VERSION 5.7 ;
  NOWIREEXTENSIONATPIN ON ;
  DIVIDERCHAR "/" ;
  BUSBITCHARS "[]" ;
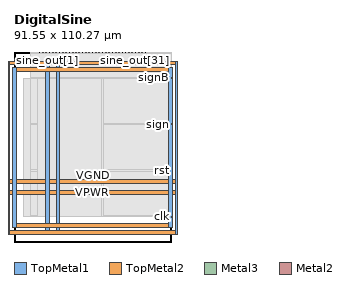
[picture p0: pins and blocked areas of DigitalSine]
MACRO DigitalSine
  CLASS BLOCK ;
  FOREIGN DigitalSine ;
  ORIGIN 0.000 0.000 ;
  SIZE 91.550 BY 110.270 ;
  PIN VGND
    DIRECTION INOUT ;
    USE GROUND ;
    PORT
      LAYER TopMetal1 ;
        RECT -4.740 4.620 -2.740 105.000 ;
    END
    PORT
      LAYER TopMetal2 ;
        RECT -4.740 4.620 95.940 6.620 ;
    END
    PORT
      LAYER TopMetal2 ;
        RECT -4.740 103.000 95.940 105.000 ;
    END
    PORT
      LAYER TopMetal1 ;
        RECT 93.940 4.620 95.940 105.000 ;
    END
    PORT
      LAYER TopMetal1 ;
        RECT 24.460 4.620 26.660 105.000 ;
    END
    PORT
      LAYER TopMetal2 ;
        RECT -4.740 33.820 95.940 36.020 ;
    END
  END VGND
  PIN VPWR
    DIRECTION INOUT ;
    USE POWER ;
    PORT
      LAYER TopMetal1 ;
        RECT -0.740 8.620 1.260 101.000 ;
    END
    PORT
      LAYER TopMetal2 ;
        RECT -0.740 8.620 91.940 10.620 ;
    END
    PORT
      LAYER TopMetal2 ;
        RECT -0.740 99.000 91.940 101.000 ;
    END
    PORT
      LAYER TopMetal1 ;
        RECT 89.940 8.620 91.940 101.000 ;
    END
    PORT
      LAYER TopMetal1 ;
        RECT 18.260 4.620 20.460 105.000 ;
    END
    PORT
      LAYER TopMetal2 ;
        RECT -4.740 27.620 95.940 29.820 ;
    END
  END VPWR
  PIN clk
    DIRECTION INPUT ;
    USE SIGNAL ;
    ANTENNAGATEAREA 0.725400 ;
    PORT
      LAYER Metal3 ;
        RECT 91.150 14.500 91.550 14.900 ;
    END
  END clk
  PIN rst
    DIRECTION INPUT ;
    USE SIGNAL ;
    ANTENNAGATEAREA 0.180700 ;
    PORT
      LAYER Metal3 ;
        RECT 91.150 41.380 91.550 41.780 ;
    END
  END rst
  PIN sign
    DIRECTION OUTPUT ;
    USE SIGNAL ;
    ANTENNADIFFAREA 0.708600 ;
    PORT
      LAYER Metal3 ;
        RECT 91.150 68.260 91.550 68.660 ;
    END
  END sign
  PIN signB
    DIRECTION OUTPUT ;
    USE SIGNAL ;
    ANTENNADIFFAREA 0.708600 ;
    PORT
      LAYER Metal3 ;
        RECT 91.150 95.140 91.550 95.540 ;
    END
  END signB
  PIN sine_out[0]
    DIRECTION OUTPUT ;
    USE SIGNAL ;
    ANTENNADIFFAREA 0.708600 ;
    PORT
      LAYER Metal2 ;
        RECT 14.680 109.870 15.080 110.270 ;
    END
  END sine_out[0]
  PIN sine_out[10]
    DIRECTION OUTPUT ;
    USE SIGNAL ;
    ANTENNADIFFAREA 0.708600 ;
    PORT
      LAYER Metal2 ;
        RECT 33.880 109.870 34.280 110.270 ;
    END
  END sine_out[10]
  PIN sine_out[11]
    DIRECTION OUTPUT ;
    USE SIGNAL ;
    ANTENNADIFFAREA 0.708600 ;
    PORT
      LAYER Metal2 ;
        RECT 35.800 109.870 36.200 110.270 ;
    END
  END sine_out[11]
  PIN sine_out[12]
    DIRECTION OUTPUT ;
    USE SIGNAL ;
    ANTENNADIFFAREA 0.708600 ;
    PORT
      LAYER Metal2 ;
        RECT 37.720 109.870 38.120 110.270 ;
    END
  END sine_out[12]
  PIN sine_out[13]
    DIRECTION OUTPUT ;
    USE SIGNAL ;
    ANTENNADIFFAREA 0.708600 ;
    PORT
      LAYER Metal2 ;
        RECT 39.640 109.870 40.040 110.270 ;
    END
  END sine_out[13]
  PIN sine_out[14]
    DIRECTION OUTPUT ;
    USE SIGNAL ;
    ANTENNADIFFAREA 0.708600 ;
    PORT
      LAYER Metal2 ;
        RECT 41.560 109.870 41.960 110.270 ;
    END
  END sine_out[14]
  PIN sine_out[15]
    DIRECTION OUTPUT ;
    USE SIGNAL ;
    ANTENNADIFFAREA 0.708600 ;
    PORT
      LAYER Metal2 ;
        RECT 43.480 109.870 43.880 110.270 ;
    END
  END sine_out[15]
  PIN sine_out[16]
    DIRECTION OUTPUT ;
    USE SIGNAL ;
    ANTENNADIFFAREA 0.708600 ;
    PORT
      LAYER Metal2 ;
        RECT 45.400 109.870 45.800 110.270 ;
    END
  END sine_out[16]
  PIN sine_out[17]
    DIRECTION OUTPUT ;
    USE SIGNAL ;
    ANTENNADIFFAREA 0.708600 ;
    PORT
      LAYER Metal2 ;
        RECT 47.320 109.870 47.720 110.270 ;
    END
  END sine_out[17]
  PIN sine_out[18]
    DIRECTION OUTPUT ;
    USE SIGNAL ;
    ANTENNADIFFAREA 0.708600 ;
    PORT
      LAYER Metal2 ;
        RECT 49.240 109.870 49.640 110.270 ;
    END
  END sine_out[18]
  PIN sine_out[19]
    DIRECTION OUTPUT ;
    USE SIGNAL ;
    ANTENNADIFFAREA 0.708600 ;
    PORT
      LAYER Metal2 ;
        RECT 51.160 109.870 51.560 110.270 ;
    END
  END sine_out[19]
  PIN sine_out[1]
    DIRECTION OUTPUT ;
    USE SIGNAL ;
    ANTENNADIFFAREA 0.708600 ;
    PORT
      LAYER Metal2 ;
        RECT 16.600 109.870 17.000 110.270 ;
    END
  END sine_out[1]
  PIN sine_out[20]
    DIRECTION OUTPUT ;
    USE SIGNAL ;
    ANTENNADIFFAREA 0.708600 ;
    PORT
      LAYER Metal2 ;
        RECT 53.080 109.870 53.480 110.270 ;
    END
  END sine_out[20]
  PIN sine_out[21]
    DIRECTION OUTPUT ;
    USE SIGNAL ;
    ANTENNADIFFAREA 0.708600 ;
    PORT
      LAYER Metal2 ;
        RECT 55.000 109.870 55.400 110.270 ;
    END
  END sine_out[21]
  PIN sine_out[22]
    DIRECTION OUTPUT ;
    USE SIGNAL ;
    ANTENNADIFFAREA 0.708600 ;
    PORT
      LAYER Metal2 ;
        RECT 56.920 109.870 57.320 110.270 ;
    END
  END sine_out[22]
  PIN sine_out[23]
    DIRECTION OUTPUT ;
    USE SIGNAL ;
    ANTENNADIFFAREA 0.708600 ;
    PORT
      LAYER Metal2 ;
        RECT 58.840 109.870 59.240 110.270 ;
    END
  END sine_out[23]
  PIN sine_out[24]
    DIRECTION OUTPUT ;
    USE SIGNAL ;
    ANTENNADIFFAREA 0.708600 ;
    PORT
      LAYER Metal2 ;
        RECT 60.760 109.870 61.160 110.270 ;
    END
  END sine_out[24]
  PIN sine_out[25]
    DIRECTION OUTPUT ;
    USE SIGNAL ;
    ANTENNADIFFAREA 0.708600 ;
    PORT
      LAYER Metal2 ;
        RECT 62.680 109.870 63.080 110.270 ;
    END
  END sine_out[25]
  PIN sine_out[26]
    DIRECTION OUTPUT ;
    USE SIGNAL ;
    ANTENNADIFFAREA 0.708600 ;
    PORT
      LAYER Metal2 ;
        RECT 64.600 109.870 65.000 110.270 ;
    END
  END sine_out[26]
  PIN sine_out[27]
    DIRECTION OUTPUT ;
    USE SIGNAL ;
    ANTENNADIFFAREA 0.708600 ;
    PORT
      LAYER Metal2 ;
        RECT 66.520 109.870 66.920 110.270 ;
    END
  END sine_out[27]
  PIN sine_out[28]
    DIRECTION OUTPUT ;
    USE SIGNAL ;
    ANTENNADIFFAREA 0.708600 ;
    PORT
      LAYER Metal2 ;
        RECT 68.440 109.870 68.840 110.270 ;
    END
  END sine_out[28]
  PIN sine_out[29]
    DIRECTION OUTPUT ;
    USE SIGNAL ;
    ANTENNADIFFAREA 0.708600 ;
    PORT
      LAYER Metal2 ;
        RECT 70.360 109.870 70.760 110.270 ;
    END
  END sine_out[29]
  PIN sine_out[2]
    DIRECTION OUTPUT ;
    USE SIGNAL ;
    ANTENNADIFFAREA 0.708600 ;
    PORT
      LAYER Metal2 ;
        RECT 18.520 109.870 18.920 110.270 ;
    END
  END sine_out[2]
  PIN sine_out[30]
    DIRECTION OUTPUT ;
    USE SIGNAL ;
    ANTENNADIFFAREA 0.708600 ;
    PORT
      LAYER Metal2 ;
        RECT 72.280 109.870 72.680 110.270 ;
    END
  END sine_out[30]
  PIN sine_out[31]
    DIRECTION OUTPUT ;
    USE SIGNAL ;
    ANTENNADIFFAREA 0.708600 ;
    PORT
      LAYER Metal2 ;
        RECT 74.200 109.870 74.600 110.270 ;
    END
  END sine_out[31]
  PIN sine_out[32]
    DIRECTION OUTPUT ;
    USE SIGNAL ;
    ANTENNADIFFAREA 0.708600 ;
    PORT
      LAYER Metal2 ;
        RECT 76.120 109.870 76.520 110.270 ;
    END
  END sine_out[32]
  PIN sine_out[3]
    DIRECTION OUTPUT ;
    USE SIGNAL ;
    ANTENNADIFFAREA 0.708600 ;
    PORT
      LAYER Metal2 ;
        RECT 20.440 109.870 20.840 110.270 ;
    END
  END sine_out[3]
  PIN sine_out[4]
    DIRECTION OUTPUT ;
    USE SIGNAL ;
    ANTENNADIFFAREA 0.708600 ;
    PORT
      LAYER Metal2 ;
        RECT 22.360 109.870 22.760 110.270 ;
    END
  END sine_out[4]
  PIN sine_out[5]
    DIRECTION OUTPUT ;
    USE SIGNAL ;
    ANTENNADIFFAREA 0.708600 ;
    PORT
      LAYER Metal2 ;
        RECT 24.280 109.870 24.680 110.270 ;
    END
  END sine_out[5]
  PIN sine_out[6]
    DIRECTION OUTPUT ;
    USE SIGNAL ;
    ANTENNADIFFAREA 0.708600 ;
    PORT
      LAYER Metal2 ;
        RECT 26.200 109.870 26.600 110.270 ;
    END
  END sine_out[6]
  PIN sine_out[7]
    DIRECTION OUTPUT ;
    USE SIGNAL ;
    ANTENNADIFFAREA 0.708600 ;
    PORT
      LAYER Metal2 ;
        RECT 28.120 109.870 28.520 110.270 ;
    END
  END sine_out[7]
  PIN sine_out[8]
    DIRECTION OUTPUT ;
    USE SIGNAL ;
    ANTENNADIFFAREA 0.708600 ;
    PORT
      LAYER Metal2 ;
        RECT 30.040 109.870 30.440 110.270 ;
    END
  END sine_out[8]
  PIN sine_out[9]
    DIRECTION OUTPUT ;
    USE SIGNAL ;
    ANTENNADIFFAREA 0.708600 ;
    PORT
      LAYER Metal2 ;
        RECT 31.960 109.870 32.360 110.270 ;
    END
  END sine_out[9]
  OBS
      LAYER GatPoly ;
        RECT 5.760 14.970 85.440 94.650 ;
      LAYER Metal1 ;
        RECT 5.760 14.900 85.440 94.720 ;
      LAYER Metal2 ;
        RECT 9.495 109.660 14.470 109.870 ;
        RECT 15.290 109.660 16.390 109.870 ;
        RECT 17.210 109.660 18.310 109.870 ;
        RECT 19.130 109.660 20.230 109.870 ;
        RECT 21.050 109.660 22.150 109.870 ;
        RECT 22.970 109.660 24.070 109.870 ;
        RECT 24.890 109.660 25.990 109.870 ;
        RECT 26.810 109.660 27.910 109.870 ;
        RECT 28.730 109.660 29.830 109.870 ;
        RECT 30.650 109.660 31.750 109.870 ;
        RECT 32.570 109.660 33.670 109.870 ;
        RECT 34.490 109.660 35.590 109.870 ;
        RECT 36.410 109.660 37.510 109.870 ;
        RECT 38.330 109.660 39.430 109.870 ;
        RECT 40.250 109.660 41.350 109.870 ;
        RECT 42.170 109.660 43.270 109.870 ;
        RECT 44.090 109.660 45.190 109.870 ;
        RECT 46.010 109.660 47.110 109.870 ;
        RECT 47.930 109.660 49.030 109.870 ;
        RECT 49.850 109.660 50.950 109.870 ;
        RECT 51.770 109.660 52.870 109.870 ;
        RECT 53.690 109.660 54.790 109.870 ;
        RECT 55.610 109.660 56.710 109.870 ;
        RECT 57.530 109.660 58.630 109.870 ;
        RECT 59.450 109.660 60.550 109.870 ;
        RECT 61.370 109.660 62.470 109.870 ;
        RECT 63.290 109.660 64.390 109.870 ;
        RECT 65.210 109.660 66.310 109.870 ;
        RECT 67.130 109.660 68.230 109.870 ;
        RECT 69.050 109.660 70.150 109.870 ;
        RECT 70.970 109.660 72.070 109.870 ;
        RECT 72.890 109.660 73.990 109.870 ;
        RECT 74.810 109.660 75.910 109.870 ;
        RECT 76.730 109.660 91.305 109.870 ;
        RECT 9.495 14.555 91.305 109.660 ;
      LAYER Metal3 ;
        RECT 9.455 95.750 91.345 99.640 ;
        RECT 9.455 94.930 90.940 95.750 ;
        RECT 9.455 68.870 91.345 94.930 ;
        RECT 9.455 68.050 90.940 68.870 ;
        RECT 9.455 41.990 91.345 68.050 ;
        RECT 9.455 41.170 90.940 41.990 ;
        RECT 9.455 15.110 91.345 41.170 ;
        RECT 9.455 14.600 90.940 15.110 ;
      LAYER Metal4 ;
        RECT 13.815 14.975 51.940 94.645 ;
      LAYER Metal5 ;
        RECT 13.775 14.810 51.025 94.810 ;
  END
END DigitalSine
END LIBRARY

